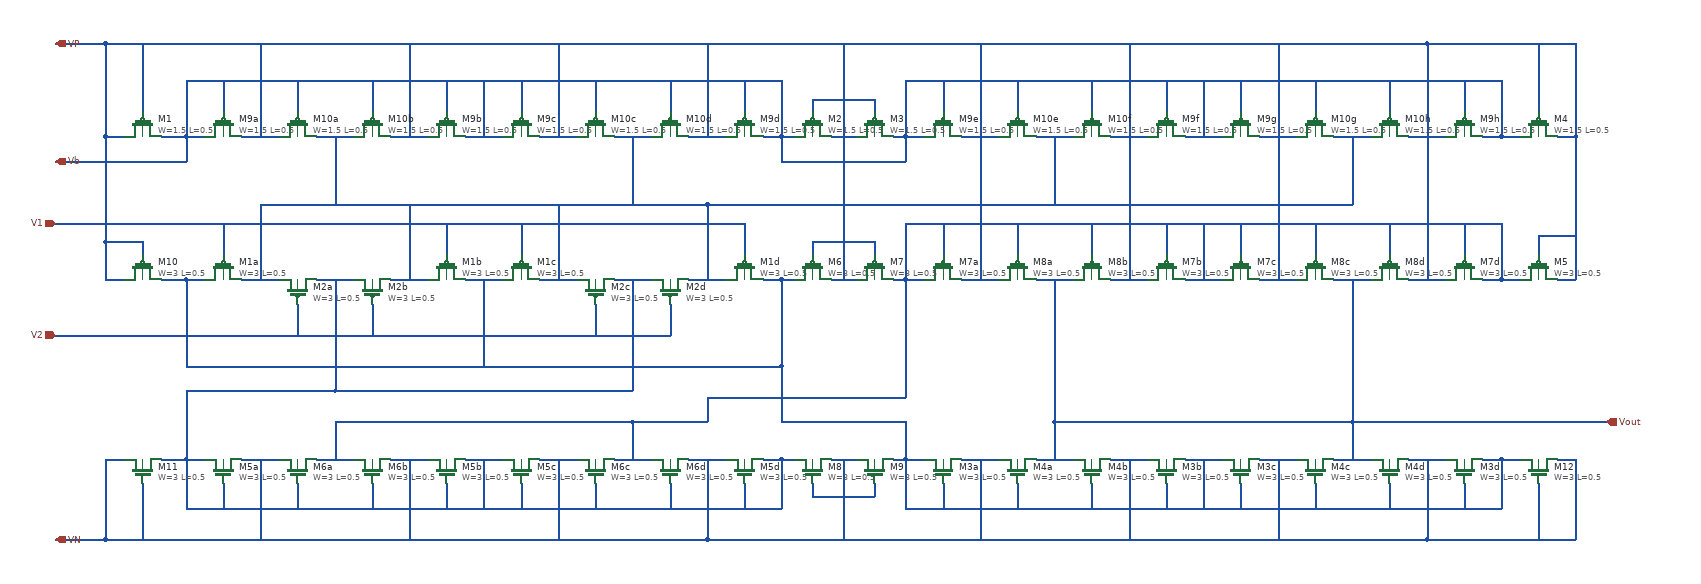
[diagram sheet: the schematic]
v {xschem version=3.4.5 file_version=1.2
}
G {}
K {}
V {}
S {}
E {}
N 470 -560 530 -560 {
lab=#net1}
N 590 -560 650 -560 {
lab=#net2}
N 710 -560 770 -560 {
lab=#net1}
N 950 -560 1010 -560 {
lab=#net1}
N 1070 -560 1130 -560 {
lab=#net2}
N 1190 -560 1260 -560 {
lab=#net1}
N 1310 -560 1340 -560 {
lab=#net3}
N 380 -560 410 -560 {
lab=#net3}
N 830 -560 890 -560 {
lab=#net3}
N 500 -680 500 -560 {
lab=#net1}
N 1220 -680 1220 -560 {
lab=#net1}
N 500 -680 1220 -680 {
lab=#net1}
N 740 -680 740 -560 {
lab=#net1}
N 980 -680 980 -560 {
lab=#net1}
N 800 -650 800 -600 {
lab=V1}
N 920 -650 920 -600 {
lab=V1}
N 1160 -520 1160 -470 {
lab=V2}
N 1040 -520 1040 -470 {
lab=V2}
N 680 -520 680 -470 {
lab=V2}
N 560 -520 560 -470 {
lab=V2}
N 1280 -650 1280 -600 {
lab=V1}
N 620 -380 1100 -380 {
lab=#net2}
N 470 -270 530 -270 {
lab=VN}
N 590 -270 650 -270 {
lab=#net4}
N 710 -270 770 -270 {
lab=VN}
N 830 -270 890 -270 {
lab=#net2}
N 950 -270 1010 -270 {
lab=VN}
N 1070 -270 1130 -270 {
lab=#net4}
N 1190 -270 1250 -270 {
lab=VN}
N 380 -270 410 -270 {
lab=#net2}
N 380 -270 380 -190 {
lab=#net2}
N 380 -190 1340 -190 {
lab=#net2}
N 1310 -270 1340 -270 {
lab=#net2}
N 1340 -270 1340 -190 {
lab=#net2}
N 440 -230 440 -190 {
lab=#net2}
N 560 -230 560 -190 {
lab=#net2}
N 680 -230 680 -190 {
lab=#net2}
N 800 -230 800 -190 {
lab=#net2}
N 920 -230 920 -190 {
lab=#net2}
N 1040 -230 1040 -190 {
lab=#net2}
N 1160 -230 1160 -190 {
lab=#net2}
N 1280 -230 1280 -190 {
lab=#net2}
N 860 -270 860 -190 {
lab=#net2}
N 1220 -270 1220 -140 {
lab=VN}
N 350 -140 1220 -140 {
lab=VN}
N 980 -270 980 -140 {
lab=VN}
N 740 -270 740 -140 {
lab=VN}
N 500 -270 500 -140 {
lab=VN}
N 620 -330 620 -270 {
lab=#net4}
N 620 -330 1100 -330 {
lab=#net4}
N 1100 -330 1100 -270 {
lab=#net4}
N 380 -380 620 -380 {
lab=#net2}
N 380 -560 380 -420 {
lab=#net3}
N 380 -420 1340 -420 {
lab=#net3}
N 1340 -560 1340 -420 {
lab=#net3}
N 860 -560 860 -420 {
lab=#net3}
N 620 -560 620 -380 {
lab=#net2}
N 380 -380 380 -270 {
lab=#net2}
N 1100 -560 1100 -380 {
lab=#net2}
N 1630 -270 1690 -270 {
lab=VN}
N 1750 -270 1810 -270 {
lab=Vout}
N 1870 -270 1930 -270 {
lab=VN}
N 1990 -270 2050 -270 {
lab=#net3}
N 2110 -270 2170 -270 {
lab=VN}
N 2230 -270 2290 -270 {
lab=Vout}
N 2350 -270 2410 -270 {
lab=VN}
N 1540 -270 1570 -270 {
lab=#net3}
N 1540 -270 1540 -190 {
lab=#net3}
N 1540 -190 2500 -190 {
lab=#net3}
N 2470 -270 2500 -270 {
lab=#net3}
N 2500 -270 2500 -190 {
lab=#net3}
N 1600 -230 1600 -190 {
lab=#net3}
N 1720 -230 1720 -190 {
lab=#net3}
N 1840 -230 1840 -190 {
lab=#net3}
N 1960 -230 1960 -190 {
lab=#net3}
N 2080 -230 2080 -190 {
lab=#net3}
N 2200 -230 2200 -190 {
lab=#net3}
N 2320 -230 2320 -190 {
lab=#net3}
N 2440 -230 2440 -190 {
lab=#net3}
N 2020 -270 2020 -190 {
lab=#net3}
N 1780 -330 1780 -270 {
lab=Vout}
N 1780 -330 2260 -330 {
lab=Vout}
N 2260 -330 2260 -270 {
lab=Vout}
N 1220 -140 2380 -140 {
lab=VN}
N 2380 -270 2380 -140 {
lab=VN}
N 2140 -270 2140 -140 {
lab=VN}
N 1900 -270 1900 -140 {
lab=VN}
N 1660 -270 1660 -140 {
lab=VN}
N 1630 -560 1690 -560 {
lab=VP}
N 1750 -560 1820 -560 {
lab=Vout}
N 1870 -560 1930 -560 {
lab=VP}
N 2110 -560 2170 -560 {
lab=VP}
N 2230 -560 2300 -560 {
lab=Vout}
N 2350 -560 2410 -560 {
lab=VP}
N 1990 -560 2050 -560 {
lab=#net4}
N 2470 -560 2500 -560 {
lab=#net4}
N 1540 -650 2500 -650 {
lab=#net4}
N 1540 -560 1570 -560 {
lab=#net4}
N 2260 -560 2260 -330 {
lab=Vout}
N 1780 -560 1780 -330 {
lab=Vout}
N 1540 -650 1540 -560 {
lab=#net4}
N 2500 -650 2500 -560 {
lab=#net4}
N 2440 -650 2440 -600 {
lab=#net4}
N 2320 -650 2320 -600 {
lab=#net4}
N 2020 -650 2020 -560 {
lab=#net4}
N 2080 -650 2080 -600 {
lab=#net4}
N 2200 -650 2200 -600 {
lab=#net4}
N 1960 -650 1960 -600 {
lab=#net4}
N 1840 -650 1840 -600 {
lab=#net4}
N 1720 -650 1720 -600 {
lab=#net4}
N 1600 -650 1600 -600 {
lab=#net4}
N 470 -790 530 -790 {
lab=VP}
N 590 -790 660 -790 {
lab=#net1}
N 710 -790 770 -790 {
lab=VP}
N 950 -790 1010 -790 {
lab=VP}
N 1070 -790 1140 -790 {
lab=#net1}
N 1190 -790 1250 -790 {
lab=VP}
N 830 -790 890 -790 {
lab=Vb}
N 1310 -790 1340 -790 {
lab=Vb}
N 380 -880 1340 -880 {
lab=Vb}
N 380 -790 410 -790 {
lab=Vb}
N 380 -880 380 -790 {
lab=Vb}
N 1340 -880 1340 -790 {
lab=Vb}
N 1280 -880 1280 -830 {
lab=Vb}
N 1160 -880 1160 -830 {
lab=Vb}
N 860 -880 860 -790 {
lab=Vb}
N 920 -880 920 -830 {
lab=Vb}
N 1040 -880 1040 -830 {
lab=Vb}
N 800 -880 800 -830 {
lab=Vb}
N 680 -880 680 -830 {
lab=Vb}
N 560 -880 560 -830 {
lab=Vb}
N 440 -880 440 -830 {
lab=Vb}
N 1630 -790 1690 -790 {
lab=VP}
N 1750 -790 1820 -790 {
lab=#net1}
N 1870 -790 1930 -790 {
lab=VP}
N 2110 -790 2170 -790 {
lab=VP}
N 2230 -790 2300 -790 {
lab=#net1}
N 2350 -790 2410 -790 {
lab=VP}
N 1990 -790 2050 -790 {
lab=Vb}
N 2470 -790 2500 -790 {
lab=Vb}
N 1540 -880 2500 -880 {
lab=Vb}
N 1540 -790 1570 -790 {
lab=Vb}
N 1540 -880 1540 -790 {
lab=Vb}
N 2500 -880 2500 -790 {
lab=Vb}
N 2440 -880 2440 -830 {
lab=Vb}
N 2320 -880 2320 -830 {
lab=Vb}
N 2020 -880 2020 -790 {
lab=Vb}
N 2080 -880 2080 -830 {
lab=Vb}
N 2200 -880 2200 -830 {
lab=Vb}
N 1960 -880 1960 -830 {
lab=Vb}
N 1840 -880 1840 -830 {
lab=Vb}
N 1720 -880 1720 -830 {
lab=Vb}
N 1600 -880 1600 -830 {
lab=Vb}
N 620 -790 620 -680 {
lab=#net1}
N 1100 -790 1100 -680 {
lab=#net1}
N 1220 -680 2260 -680 {
lab=#net1}
N 2260 -790 2260 -680 {
lab=#net1}
N 1780 -790 1780 -680 {
lab=#net1}
N 1340 -790 1340 -750 {
lab=Vb}
N 1340 -750 1540 -750 {
lab=Vb}
N 1540 -790 1540 -750 {
lab=Vb}
N 380 -790 380 -750 {
lab=Vb}
N 350 -940 2380 -940 {
lab=VP}
N 2380 -940 2380 -790 {
lab=VP}
N 2380 -790 2380 -560 {
lab=VP}
N 2140 -940 2140 -790 {
lab=VP}
N 2140 -790 2140 -560 {
lab=VP}
N 1900 -940 1900 -790 {
lab=VP}
N 1900 -790 1900 -560 {
lab=VP}
N 1660 -790 1660 -560 {
lab=VP}
N 1660 -940 1660 -790 {
lab=VP}
N 1220 -940 1220 -790 {
lab=VP}
N 980 -940 980 -790 {
lab=VP}
N 740 -940 740 -790 {
lab=VP}
N 500 -940 500 -790 {
lab=VP}
N 340 -790 380 -790 {
lab=Vb}
N 250 -940 350 -940 {
lab=VP}
N 310 -940 310 -830 {
lab=VP}
N 250 -140 350 -140 {
lab=VN}
N 1420 -790 1460 -790 {
lab=VP}
N 1520 -790 1540 -790 {
lab=Vb}
N 1340 -790 1360 -790 {
lab=Vb}
N 1390 -850 1390 -830 {
lab=VP}
N 1390 -850 1490 -850 {
lab=VP}
N 1490 -850 1490 -830 {
lab=VP}
N 1440 -850 1440 -790 {
lab=VP}
N 1440 -940 1440 -850 {
lab=VP}
N 2500 -790 2530 -790 {
lab=Vb}
N 2590 -790 2620 -790 {
lab=VP}
N 2380 -940 2620 -940 {
lab=VP}
N 2620 -940 2620 -790 {
lab=VP}
N 2560 -940 2560 -830 {
lab=VP}
N 2500 -560 2530 -560 {
lab=#net4}
N 2590 -560 2620 -560 {
lab=VP}
N 2620 -790 2620 -560 {
lab=VP}
N 2560 -630 2560 -600 {
lab=VP}
N 2560 -630 2620 -630 {
lab=VP}
N 1420 -560 1460 -560 {
lab=VP}
N 1520 -560 1540 -560 {
lab=#net4}
N 1340 -560 1360 -560 {
lab=#net3}
N 1390 -620 1390 -600 {
lab=VP}
N 1390 -620 1490 -620 {
lab=VP}
N 1490 -620 1490 -600 {
lab=VP}
N 1440 -620 1440 -560 {
lab=VP}
N 1440 -790 1440 -620 {
lab=VP}
N 1340 -270 1360 -270 {
lab=#net2}
N 1520 -270 1540 -270 {
lab=#net3}
N 1420 -270 1460 -270 {
lab=VN}
N 1390 -230 1390 -210 {
lab=VN}
N 1390 -210 1490 -210 {
lab=VN}
N 1490 -230 1490 -210 {
lab=VN}
N 1440 -270 1440 -210 {
lab=VN}
N 1440 -210 1440 -140 {
lab=VN}
N 1100 -330 1220 -330 {
lab=#net4}
N 1220 -370 1220 -330 {
lab=#net4}
N 1220 -370 1540 -370 {
lab=#net4}
N 1540 -560 1540 -370 {
lab=#net4}
N 1340 -420 1340 -330 {
lab=#net3}
N 1340 -330 1540 -330 {
lab=#net3}
N 1540 -330 1540 -270 {
lab=#net3}
N 250 -270 280 -270 {
lab=VN}
N 340 -270 380 -270 {
lab=#net2}
N 340 -560 380 -560 {
lab=#net3}
N 250 -560 280 -560 {
lab=VP}
N 250 -620 250 -560 {
lab=VP}
N 250 -620 310 -620 {
lab=VP}
N 310 -620 310 -600 {
lab=VP}
N 170 -940 250 -940 {
lab=VP}
N 170 -140 250 -140 {
lab=VN}
N 250 -790 280 -790 {
lab=VP}
N 250 -940 250 -790 {
lab=VP}
N 250 -790 250 -620 {
lab=VP}
N 170 -750 380 -750 {
lab=Vb}
N 310 -230 310 -140 {
lab=VN}
N 250 -270 250 -140 {
lab=VN}
N 2500 -270 2530 -270 {
lab=#net3}
N 2590 -270 2620 -270 {
lab=VN}
N 2620 -270 2620 -140 {
lab=VN}
N 2380 -140 2620 -140 {
lab=VN}
N 2560 -230 2560 -140 {
lab=VN}
N 2260 -330 2670 -330 {
lab=Vout}
N 170 -650 1280 -650 {
lab=V1}
N 170 -470 1160 -470 {
lab=V2}
N 440 -650 440 -600 {
lab=V1}
C {sky130_fd_pr/pfet3_01v8.sym} 440 -580 1 0 {name=M1a
L=0.5
W=3
body=VP
nf=1
mult=1
ad="'int((nf+1)/2) * W/nf * 0.29'" 
pd="'2*int((nf+1)/2) * (W/nf + 0.29)'"
as="'int((nf+2)/2) * W/nf * 0.29'" 
ps="'2*int((nf+2)/2) * (W/nf + 0.29)'"
nrd="'0.29 / W'" nrs="'0.29 / W'"
sa=0 sb=0 sd=0
model=pfet_01v8
spiceprefix=X
}
C {sky130_fd_pr/pfet3_01v8.sym} 560 -540 3 0 {name=M2a
L=0.5
W=3
body=VP
nf=1
mult=1
ad="'int((nf+1)/2) * W/nf * 0.29'" 
pd="'2*int((nf+1)/2) * (W/nf + 0.29)'"
as="'int((nf+2)/2) * W/nf * 0.29'" 
ps="'2*int((nf+2)/2) * (W/nf + 0.29)'"
nrd="'0.29 / W'" nrs="'0.29 / W'"
sa=0 sb=0 sd=0
model=pfet_01v8
spiceprefix=X
}
C {sky130_fd_pr/pfet3_01v8.sym} 680 -540 3 0 {name=M2b
L=0.5
W=3
body=VP
nf=1
mult=1
ad="'int((nf+1)/2) * W/nf * 0.29'" 
pd="'2*int((nf+1)/2) * (W/nf + 0.29)'"
as="'int((nf+2)/2) * W/nf * 0.29'" 
ps="'2*int((nf+2)/2) * (W/nf + 0.29)'"
nrd="'0.29 / W'" nrs="'0.29 / W'"
sa=0 sb=0 sd=0
model=pfet_01v8
spiceprefix=X
}
C {sky130_fd_pr/pfet3_01v8.sym} 800 -580 1 0 {name=M1b
L=0.5
W=3
body=VP
nf=1
mult=1
ad="'int((nf+1)/2) * W/nf * 0.29'" 
pd="'2*int((nf+1)/2) * (W/nf + 0.29)'"
as="'int((nf+2)/2) * W/nf * 0.29'" 
ps="'2*int((nf+2)/2) * (W/nf + 0.29)'"
nrd="'0.29 / W'" nrs="'0.29 / W'"
sa=0 sb=0 sd=0
model=pfet_01v8
spiceprefix=X
}
C {sky130_fd_pr/pfet3_01v8.sym} 920 -580 1 0 {name=M1c
L=0.5
W=3
body=VP
nf=1
mult=1
ad="'int((nf+1)/2) * W/nf * 0.29'" 
pd="'2*int((nf+1)/2) * (W/nf + 0.29)'"
as="'int((nf+2)/2) * W/nf * 0.29'" 
ps="'2*int((nf+2)/2) * (W/nf + 0.29)'"
nrd="'0.29 / W'" nrs="'0.29 / W'"
sa=0 sb=0 sd=0
model=pfet_01v8
spiceprefix=X
}
C {sky130_fd_pr/pfet3_01v8.sym} 1040 -540 3 0 {name=M2c
L=0.5
W=3
body=VP
nf=1
mult=1
ad="'int((nf+1)/2) * W/nf * 0.29'" 
pd="'2*int((nf+1)/2) * (W/nf + 0.29)'"
as="'int((nf+2)/2) * W/nf * 0.29'" 
ps="'2*int((nf+2)/2) * (W/nf + 0.29)'"
nrd="'0.29 / W'" nrs="'0.29 / W'"
sa=0 sb=0 sd=0
model=pfet_01v8
spiceprefix=X
}
C {sky130_fd_pr/pfet3_01v8.sym} 1160 -540 3 0 {name=M2d
L=0.5
W=3
body=VP
nf=1
mult=1
ad="'int((nf+1)/2) * W/nf * 0.29'" 
pd="'2*int((nf+1)/2) * (W/nf + 0.29)'"
as="'int((nf+2)/2) * W/nf * 0.29'" 
ps="'2*int((nf+2)/2) * (W/nf + 0.29)'"
nrd="'0.29 / W'" nrs="'0.29 / W'"
sa=0 sb=0 sd=0
model=pfet_01v8
spiceprefix=X
}
C {sky130_fd_pr/pfet3_01v8.sym} 1280 -580 1 0 {name=M1d
L=0.5
W=3
body=VP
nf=1
mult=1
ad="'int((nf+1)/2) * W/nf * 0.29'" 
pd="'2*int((nf+1)/2) * (W/nf + 0.29)'"
as="'int((nf+2)/2) * W/nf * 0.29'" 
ps="'2*int((nf+2)/2) * (W/nf + 0.29)'"
nrd="'0.29 / W'" nrs="'0.29 / W'"
sa=0 sb=0 sd=0
model=pfet_01v8
spiceprefix=X
}
C {sky130_fd_pr/nfet3_01v8.sym} 440 -250 3 0 {name=M5a
L=0.5
W=3
body=VN
nf=1
mult=1
ad="'int((nf+1)/2) * W/nf * 0.29'" 
pd="'2*int((nf+1)/2) * (W/nf + 0.29)'"
as="'int((nf+2)/2) * W/nf * 0.29'" 
ps="'2*int((nf+2)/2) * (W/nf + 0.29)'"
nrd="'0.29 / W'" nrs="'0.29 / W'"
sa=0 sb=0 sd=0
model=nfet_01v8
spiceprefix=X
}
C {sky130_fd_pr/nfet3_01v8.sym} 560 -250 3 0 {name=M6a
L=0.5
W=3
body=VN
nf=1
mult=1
ad="'int((nf+1)/2) * W/nf * 0.29'" 
pd="'2*int((nf+1)/2) * (W/nf + 0.29)'"
as="'int((nf+2)/2) * W/nf * 0.29'" 
ps="'2*int((nf+2)/2) * (W/nf + 0.29)'"
nrd="'0.29 / W'" nrs="'0.29 / W'"
sa=0 sb=0 sd=0
model=nfet_01v8
spiceprefix=X
}
C {sky130_fd_pr/nfet3_01v8.sym} 680 -250 3 0 {name=M6b
L=0.5
W=3
body=VN
nf=1
mult=1
ad="'int((nf+1)/2) * W/nf * 0.29'" 
pd="'2*int((nf+1)/2) * (W/nf + 0.29)'"
as="'int((nf+2)/2) * W/nf * 0.29'" 
ps="'2*int((nf+2)/2) * (W/nf + 0.29)'"
nrd="'0.29 / W'" nrs="'0.29 / W'"
sa=0 sb=0 sd=0
model=nfet_01v8
spiceprefix=X
}
C {sky130_fd_pr/nfet3_01v8.sym} 800 -250 3 0 {name=M5b
L=0.5
W=3
body=VN
nf=1
mult=1
ad="'int((nf+1)/2) * W/nf * 0.29'" 
pd="'2*int((nf+1)/2) * (W/nf + 0.29)'"
as="'int((nf+2)/2) * W/nf * 0.29'" 
ps="'2*int((nf+2)/2) * (W/nf + 0.29)'"
nrd="'0.29 / W'" nrs="'0.29 / W'"
sa=0 sb=0 sd=0
model=nfet_01v8
spiceprefix=X
}
C {sky130_fd_pr/nfet3_01v8.sym} 920 -250 3 0 {name=M5c
L=0.5
W=3
body=VN
nf=1
mult=1
ad="'int((nf+1)/2) * W/nf * 0.29'" 
pd="'2*int((nf+1)/2) * (W/nf + 0.29)'"
as="'int((nf+2)/2) * W/nf * 0.29'" 
ps="'2*int((nf+2)/2) * (W/nf + 0.29)'"
nrd="'0.29 / W'" nrs="'0.29 / W'"
sa=0 sb=0 sd=0
model=nfet_01v8
spiceprefix=X
}
C {sky130_fd_pr/nfet3_01v8.sym} 1040 -250 3 0 {name=M6c
L=0.5
W=3
body=VN
nf=1
mult=1
ad="'int((nf+1)/2) * W/nf * 0.29'" 
pd="'2*int((nf+1)/2) * (W/nf + 0.29)'"
as="'int((nf+2)/2) * W/nf * 0.29'" 
ps="'2*int((nf+2)/2) * (W/nf + 0.29)'"
nrd="'0.29 / W'" nrs="'0.29 / W'"
sa=0 sb=0 sd=0
model=nfet_01v8
spiceprefix=X
}
C {sky130_fd_pr/nfet3_01v8.sym} 1160 -250 3 0 {name=M6d
L=0.5
W=3
body=VN
nf=1
mult=1
ad="'int((nf+1)/2) * W/nf * 0.29'" 
pd="'2*int((nf+1)/2) * (W/nf + 0.29)'"
as="'int((nf+2)/2) * W/nf * 0.29'" 
ps="'2*int((nf+2)/2) * (W/nf + 0.29)'"
nrd="'0.29 / W'" nrs="'0.29 / W'"
sa=0 sb=0 sd=0
model=nfet_01v8
spiceprefix=X
}
C {sky130_fd_pr/nfet3_01v8.sym} 1280 -250 3 0 {name=M5d
L=0.5
W=3
body=VN
nf=1
mult=1
ad="'int((nf+1)/2) * W/nf * 0.29'" 
pd="'2*int((nf+1)/2) * (W/nf + 0.29)'"
as="'int((nf+2)/2) * W/nf * 0.29'" 
ps="'2*int((nf+2)/2) * (W/nf + 0.29)'"
nrd="'0.29 / W'" nrs="'0.29 / W'"
sa=0 sb=0 sd=0
model=nfet_01v8
spiceprefix=X
}
C {sky130_fd_pr/nfet3_01v8.sym} 1600 -250 3 0 {name=M3a
L=0.5
W=3
body=VN
nf=1
mult=1
ad="'int((nf+1)/2) * W/nf * 0.29'" 
pd="'2*int((nf+1)/2) * (W/nf + 0.29)'"
as="'int((nf+2)/2) * W/nf * 0.29'" 
ps="'2*int((nf+2)/2) * (W/nf + 0.29)'"
nrd="'0.29 / W'" nrs="'0.29 / W'"
sa=0 sb=0 sd=0
model=nfet_01v8
spiceprefix=X
}
C {sky130_fd_pr/nfet3_01v8.sym} 1720 -250 3 0 {name=M4a
L=0.5
W=3
body=VN
nf=1
mult=1
ad="'int((nf+1)/2) * W/nf * 0.29'" 
pd="'2*int((nf+1)/2) * (W/nf + 0.29)'"
as="'int((nf+2)/2) * W/nf * 0.29'" 
ps="'2*int((nf+2)/2) * (W/nf + 0.29)'"
nrd="'0.29 / W'" nrs="'0.29 / W'"
sa=0 sb=0 sd=0
model=nfet_01v8
spiceprefix=X
}
C {sky130_fd_pr/nfet3_01v8.sym} 1840 -250 3 0 {name=M4b
L=0.5
W=3
body=VN
nf=1
mult=1
ad="'int((nf+1)/2) * W/nf * 0.29'" 
pd="'2*int((nf+1)/2) * (W/nf + 0.29)'"
as="'int((nf+2)/2) * W/nf * 0.29'" 
ps="'2*int((nf+2)/2) * (W/nf + 0.29)'"
nrd="'0.29 / W'" nrs="'0.29 / W'"
sa=0 sb=0 sd=0
model=nfet_01v8
spiceprefix=X
}
C {sky130_fd_pr/nfet3_01v8.sym} 1960 -250 3 0 {name=M3b
L=0.5
W=3
body=VN
nf=1
mult=1
ad="'int((nf+1)/2) * W/nf * 0.29'" 
pd="'2*int((nf+1)/2) * (W/nf + 0.29)'"
as="'int((nf+2)/2) * W/nf * 0.29'" 
ps="'2*int((nf+2)/2) * (W/nf + 0.29)'"
nrd="'0.29 / W'" nrs="'0.29 / W'"
sa=0 sb=0 sd=0
model=nfet_01v8
spiceprefix=X
}
C {sky130_fd_pr/nfet3_01v8.sym} 2080 -250 3 0 {name=M3c
L=0.5
W=3
body=VN
nf=1
mult=1
ad="'int((nf+1)/2) * W/nf * 0.29'" 
pd="'2*int((nf+1)/2) * (W/nf + 0.29)'"
as="'int((nf+2)/2) * W/nf * 0.29'" 
ps="'2*int((nf+2)/2) * (W/nf + 0.29)'"
nrd="'0.29 / W'" nrs="'0.29 / W'"
sa=0 sb=0 sd=0
model=nfet_01v8
spiceprefix=X
}
C {sky130_fd_pr/nfet3_01v8.sym} 2200 -250 3 0 {name=M4c
L=0.5
W=3
body=VN
nf=1
mult=1
ad="'int((nf+1)/2) * W/nf * 0.29'" 
pd="'2*int((nf+1)/2) * (W/nf + 0.29)'"
as="'int((nf+2)/2) * W/nf * 0.29'" 
ps="'2*int((nf+2)/2) * (W/nf + 0.29)'"
nrd="'0.29 / W'" nrs="'0.29 / W'"
sa=0 sb=0 sd=0
model=nfet_01v8
spiceprefix=X
}
C {sky130_fd_pr/nfet3_01v8.sym} 2320 -250 3 0 {name=M4d
L=0.5
W=3
body=VN
nf=1
mult=1
ad="'int((nf+1)/2) * W/nf * 0.29'" 
pd="'2*int((nf+1)/2) * (W/nf + 0.29)'"
as="'int((nf+2)/2) * W/nf * 0.29'" 
ps="'2*int((nf+2)/2) * (W/nf + 0.29)'"
nrd="'0.29 / W'" nrs="'0.29 / W'"
sa=0 sb=0 sd=0
model=nfet_01v8
spiceprefix=X
}
C {sky130_fd_pr/nfet3_01v8.sym} 2440 -250 3 0 {name=M3d
L=0.5
W=3
body=VN
nf=1
mult=1
ad="'int((nf+1)/2) * W/nf * 0.29'" 
pd="'2*int((nf+1)/2) * (W/nf + 0.29)'"
as="'int((nf+2)/2) * W/nf * 0.29'" 
ps="'2*int((nf+2)/2) * (W/nf + 0.29)'"
nrd="'0.29 / W'" nrs="'0.29 / W'"
sa=0 sb=0 sd=0
model=nfet_01v8
spiceprefix=X
}
C {sky130_fd_pr/pfet3_01v8.sym} 1600 -580 1 0 {name=M7a
L=0.5
W=3
body=VP
nf=1
mult=1
ad="'int((nf+1)/2) * W/nf * 0.29'" 
pd="'2*int((nf+1)/2) * (W/nf + 0.29)'"
as="'int((nf+2)/2) * W/nf * 0.29'" 
ps="'2*int((nf+2)/2) * (W/nf + 0.29)'"
nrd="'0.29 / W'" nrs="'0.29 / W'"
sa=0 sb=0 sd=0
model=pfet_01v8
spiceprefix=X
}
C {sky130_fd_pr/pfet3_01v8.sym} 1720 -580 1 0 {name=M8a
L=0.5
W=3
body=VP
nf=1
mult=1
ad="'int((nf+1)/2) * W/nf * 0.29'" 
pd="'2*int((nf+1)/2) * (W/nf + 0.29)'"
as="'int((nf+2)/2) * W/nf * 0.29'" 
ps="'2*int((nf+2)/2) * (W/nf + 0.29)'"
nrd="'0.29 / W'" nrs="'0.29 / W'"
sa=0 sb=0 sd=0
model=pfet_01v8
spiceprefix=X
}
C {sky130_fd_pr/pfet3_01v8.sym} 1840 -580 1 0 {name=M8b
L=0.5
W=3
body=VP
nf=1
mult=1
ad="'int((nf+1)/2) * W/nf * 0.29'" 
pd="'2*int((nf+1)/2) * (W/nf + 0.29)'"
as="'int((nf+2)/2) * W/nf * 0.29'" 
ps="'2*int((nf+2)/2) * (W/nf + 0.29)'"
nrd="'0.29 / W'" nrs="'0.29 / W'"
sa=0 sb=0 sd=0
model=pfet_01v8
spiceprefix=X
}
C {sky130_fd_pr/pfet3_01v8.sym} 1960 -580 1 0 {name=M7b
L=0.5
W=3
body=VP
nf=1
mult=1
ad="'int((nf+1)/2) * W/nf * 0.29'" 
pd="'2*int((nf+1)/2) * (W/nf + 0.29)'"
as="'int((nf+2)/2) * W/nf * 0.29'" 
ps="'2*int((nf+2)/2) * (W/nf + 0.29)'"
nrd="'0.29 / W'" nrs="'0.29 / W'"
sa=0 sb=0 sd=0
model=pfet_01v8
spiceprefix=X
}
C {sky130_fd_pr/pfet3_01v8.sym} 2080 -580 1 0 {name=M7c
L=0.5
W=3
body=VP
nf=1
mult=1
ad="'int((nf+1)/2) * W/nf * 0.29'" 
pd="'2*int((nf+1)/2) * (W/nf + 0.29)'"
as="'int((nf+2)/2) * W/nf * 0.29'" 
ps="'2*int((nf+2)/2) * (W/nf + 0.29)'"
nrd="'0.29 / W'" nrs="'0.29 / W'"
sa=0 sb=0 sd=0
model=pfet_01v8
spiceprefix=X
}
C {sky130_fd_pr/pfet3_01v8.sym} 2200 -580 1 0 {name=M8c
L=0.5
W=3
body=VP
nf=1
mult=1
ad="'int((nf+1)/2) * W/nf * 0.29'" 
pd="'2*int((nf+1)/2) * (W/nf + 0.29)'"
as="'int((nf+2)/2) * W/nf * 0.29'" 
ps="'2*int((nf+2)/2) * (W/nf + 0.29)'"
nrd="'0.29 / W'" nrs="'0.29 / W'"
sa=0 sb=0 sd=0
model=pfet_01v8
spiceprefix=X
}
C {sky130_fd_pr/pfet3_01v8.sym} 2320 -580 1 0 {name=M8d
L=0.5
W=3
body=VP
nf=1
mult=1
ad="'int((nf+1)/2) * W/nf * 0.29'" 
pd="'2*int((nf+1)/2) * (W/nf + 0.29)'"
as="'int((nf+2)/2) * W/nf * 0.29'" 
ps="'2*int((nf+2)/2) * (W/nf + 0.29)'"
nrd="'0.29 / W'" nrs="'0.29 / W'"
sa=0 sb=0 sd=0
model=pfet_01v8
spiceprefix=X
}
C {sky130_fd_pr/pfet3_01v8.sym} 2440 -580 1 0 {name=M7d
L=0.5
W=3
body=VP
nf=1
mult=1
ad="'int((nf+1)/2) * W/nf * 0.29'" 
pd="'2*int((nf+1)/2) * (W/nf + 0.29)'"
as="'int((nf+2)/2) * W/nf * 0.29'" 
ps="'2*int((nf+2)/2) * (W/nf + 0.29)'"
nrd="'0.29 / W'" nrs="'0.29 / W'"
sa=0 sb=0 sd=0
model=pfet_01v8
spiceprefix=X
}
C {sky130_fd_pr/pfet3_01v8.sym} 440 -810 1 0 {name=M9a
L=0.5
W=1.5
body=VP
nf=1
mult=1
ad="'int((nf+1)/2) * W/nf * 0.29'" 
pd="'2*int((nf+1)/2) * (W/nf + 0.29)'"
as="'int((nf+2)/2) * W/nf * 0.29'" 
ps="'2*int((nf+2)/2) * (W/nf + 0.29)'"
nrd="'0.29 / W'" nrs="'0.29 / W'"
sa=0 sb=0 sd=0
model=pfet_01v8
spiceprefix=X
}
C {sky130_fd_pr/pfet3_01v8.sym} 560 -810 1 0 {name=M10a
L=0.5
W=1.5
body=VP
nf=1
mult=1
ad="'int((nf+1)/2) * W/nf * 0.29'" 
pd="'2*int((nf+1)/2) * (W/nf + 0.29)'"
as="'int((nf+2)/2) * W/nf * 0.29'" 
ps="'2*int((nf+2)/2) * (W/nf + 0.29)'"
nrd="'0.29 / W'" nrs="'0.29 / W'"
sa=0 sb=0 sd=0
model=pfet_01v8
spiceprefix=X
}
C {sky130_fd_pr/pfet3_01v8.sym} 680 -810 1 0 {name=M10b
L=0.5
W=1.5
body=VP
nf=1
mult=1
ad="'int((nf+1)/2) * W/nf * 0.29'" 
pd="'2*int((nf+1)/2) * (W/nf + 0.29)'"
as="'int((nf+2)/2) * W/nf * 0.29'" 
ps="'2*int((nf+2)/2) * (W/nf + 0.29)'"
nrd="'0.29 / W'" nrs="'0.29 / W'"
sa=0 sb=0 sd=0
model=pfet_01v8
spiceprefix=X
}
C {sky130_fd_pr/pfet3_01v8.sym} 800 -810 1 0 {name=M9b
L=0.5
W=1.5
body=VP
nf=1
mult=1
ad="'int((nf+1)/2) * W/nf * 0.29'" 
pd="'2*int((nf+1)/2) * (W/nf + 0.29)'"
as="'int((nf+2)/2) * W/nf * 0.29'" 
ps="'2*int((nf+2)/2) * (W/nf + 0.29)'"
nrd="'0.29 / W'" nrs="'0.29 / W'"
sa=0 sb=0 sd=0
model=pfet_01v8
spiceprefix=X
}
C {sky130_fd_pr/pfet3_01v8.sym} 920 -810 1 0 {name=M9c
L=0.5
W=1.5
body=VP
nf=1
mult=1
ad="'int((nf+1)/2) * W/nf * 0.29'" 
pd="'2*int((nf+1)/2) * (W/nf + 0.29)'"
as="'int((nf+2)/2) * W/nf * 0.29'" 
ps="'2*int((nf+2)/2) * (W/nf + 0.29)'"
nrd="'0.29 / W'" nrs="'0.29 / W'"
sa=0 sb=0 sd=0
model=pfet_01v8
spiceprefix=X
}
C {sky130_fd_pr/pfet3_01v8.sym} 1040 -810 1 0 {name=M10c
L=0.5
W=1.5
body=VP
nf=1
mult=1
ad="'int((nf+1)/2) * W/nf * 0.29'" 
pd="'2*int((nf+1)/2) * (W/nf + 0.29)'"
as="'int((nf+2)/2) * W/nf * 0.29'" 
ps="'2*int((nf+2)/2) * (W/nf + 0.29)'"
nrd="'0.29 / W'" nrs="'0.29 / W'"
sa=0 sb=0 sd=0
model=pfet_01v8
spiceprefix=X
}
C {sky130_fd_pr/pfet3_01v8.sym} 1160 -810 1 0 {name=M10d
L=0.5
W=1.5
body=VP
nf=1
mult=1
ad="'int((nf+1)/2) * W/nf * 0.29'" 
pd="'2*int((nf+1)/2) * (W/nf + 0.29)'"
as="'int((nf+2)/2) * W/nf * 0.29'" 
ps="'2*int((nf+2)/2) * (W/nf + 0.29)'"
nrd="'0.29 / W'" nrs="'0.29 / W'"
sa=0 sb=0 sd=0
model=pfet_01v8
spiceprefix=X
}
C {sky130_fd_pr/pfet3_01v8.sym} 1280 -810 1 0 {name=M9d
L=0.5
W=1.5
body=VP
nf=1
mult=1
ad="'int((nf+1)/2) * W/nf * 0.29'" 
pd="'2*int((nf+1)/2) * (W/nf + 0.29)'"
as="'int((nf+2)/2) * W/nf * 0.29'" 
ps="'2*int((nf+2)/2) * (W/nf + 0.29)'"
nrd="'0.29 / W'" nrs="'0.29 / W'"
sa=0 sb=0 sd=0
model=pfet_01v8
spiceprefix=X
}
C {sky130_fd_pr/pfet3_01v8.sym} 1600 -810 1 0 {name=M9e
L=0.5
W=1.5
body=VP
nf=1
mult=1
ad="'int((nf+1)/2) * W/nf * 0.29'" 
pd="'2*int((nf+1)/2) * (W/nf + 0.29)'"
as="'int((nf+2)/2) * W/nf * 0.29'" 
ps="'2*int((nf+2)/2) * (W/nf + 0.29)'"
nrd="'0.29 / W'" nrs="'0.29 / W'"
sa=0 sb=0 sd=0
model=pfet_01v8
spiceprefix=X
}
C {sky130_fd_pr/pfet3_01v8.sym} 1720 -810 1 0 {name=M10e
L=0.5
W=1.5
body=VP
nf=1
mult=1
ad="'int((nf+1)/2) * W/nf * 0.29'" 
pd="'2*int((nf+1)/2) * (W/nf + 0.29)'"
as="'int((nf+2)/2) * W/nf * 0.29'" 
ps="'2*int((nf+2)/2) * (W/nf + 0.29)'"
nrd="'0.29 / W'" nrs="'0.29 / W'"
sa=0 sb=0 sd=0
model=pfet_01v8
spiceprefix=X
}
C {sky130_fd_pr/pfet3_01v8.sym} 1840 -810 1 0 {name=M10f
L=0.5
W=1.5
body=VP
nf=1
mult=1
ad="'int((nf+1)/2) * W/nf * 0.29'" 
pd="'2*int((nf+1)/2) * (W/nf + 0.29)'"
as="'int((nf+2)/2) * W/nf * 0.29'" 
ps="'2*int((nf+2)/2) * (W/nf + 0.29)'"
nrd="'0.29 / W'" nrs="'0.29 / W'"
sa=0 sb=0 sd=0
model=pfet_01v8
spiceprefix=X
}
C {sky130_fd_pr/pfet3_01v8.sym} 1960 -810 1 0 {name=M9f
L=0.5
W=1.5
body=VP
nf=1
mult=1
ad="'int((nf+1)/2) * W/nf * 0.29'" 
pd="'2*int((nf+1)/2) * (W/nf + 0.29)'"
as="'int((nf+2)/2) * W/nf * 0.29'" 
ps="'2*int((nf+2)/2) * (W/nf + 0.29)'"
nrd="'0.29 / W'" nrs="'0.29 / W'"
sa=0 sb=0 sd=0
model=pfet_01v8
spiceprefix=X
}
C {sky130_fd_pr/pfet3_01v8.sym} 2080 -810 1 0 {name=M9g
L=0.5
W=1.5
body=VP
nf=1
mult=1
ad="'int((nf+1)/2) * W/nf * 0.29'" 
pd="'2*int((nf+1)/2) * (W/nf + 0.29)'"
as="'int((nf+2)/2) * W/nf * 0.29'" 
ps="'2*int((nf+2)/2) * (W/nf + 0.29)'"
nrd="'0.29 / W'" nrs="'0.29 / W'"
sa=0 sb=0 sd=0
model=pfet_01v8
spiceprefix=X
}
C {sky130_fd_pr/pfet3_01v8.sym} 2200 -810 1 0 {name=M10g
L=0.5
W=1.5
body=VP
nf=1
mult=1
ad="'int((nf+1)/2) * W/nf * 0.29'" 
pd="'2*int((nf+1)/2) * (W/nf + 0.29)'"
as="'int((nf+2)/2) * W/nf * 0.29'" 
ps="'2*int((nf+2)/2) * (W/nf + 0.29)'"
nrd="'0.29 / W'" nrs="'0.29 / W'"
sa=0 sb=0 sd=0
model=pfet_01v8
spiceprefix=X
}
C {sky130_fd_pr/pfet3_01v8.sym} 2320 -810 1 0 {name=M10h
L=0.5
W=1.5
body=VP
nf=1
mult=1
ad="'int((nf+1)/2) * W/nf * 0.29'" 
pd="'2*int((nf+1)/2) * (W/nf + 0.29)'"
as="'int((nf+2)/2) * W/nf * 0.29'" 
ps="'2*int((nf+2)/2) * (W/nf + 0.29)'"
nrd="'0.29 / W'" nrs="'0.29 / W'"
sa=0 sb=0 sd=0
model=pfet_01v8
spiceprefix=X
}
C {sky130_fd_pr/pfet3_01v8.sym} 2440 -810 1 0 {name=M9h
L=0.5
W=1.5
body=VP
nf=1
mult=1
ad="'int((nf+1)/2) * W/nf * 0.29'" 
pd="'2*int((nf+1)/2) * (W/nf + 0.29)'"
as="'int((nf+2)/2) * W/nf * 0.29'" 
ps="'2*int((nf+2)/2) * (W/nf + 0.29)'"
nrd="'0.29 / W'" nrs="'0.29 / W'"
sa=0 sb=0 sd=0
model=pfet_01v8
spiceprefix=X
}
C {sky130_fd_pr/pfet3_01v8.sym} 310 -810 1 0 {name=M1
L=0.5
W=1.5
body=VP
nf=1
mult=1
ad="'int((nf+1)/2) * W/nf * 0.29'" 
pd="'2*int((nf+1)/2) * (W/nf + 0.29)'"
as="'int((nf+2)/2) * W/nf * 0.29'" 
ps="'2*int((nf+2)/2) * (W/nf + 0.29)'"
nrd="'0.29 / W'" nrs="'0.29 / W'"
sa=0 sb=0 sd=0
model=pfet_01v8
spiceprefix=X
}
C {sky130_fd_pr/pfet3_01v8.sym} 1390 -810 1 0 {name=M2
L=0.5
W=1.5
body=VP
nf=1
mult=1
ad="'int((nf+1)/2) * W/nf * 0.29'" 
pd="'2*int((nf+1)/2) * (W/nf + 0.29)'"
as="'int((nf+2)/2) * W/nf * 0.29'" 
ps="'2*int((nf+2)/2) * (W/nf + 0.29)'"
nrd="'0.29 / W'" nrs="'0.29 / W'"
sa=0 sb=0 sd=0
model=pfet_01v8
spiceprefix=X
}
C {sky130_fd_pr/pfet3_01v8.sym} 1490 -810 1 0 {name=M3
L=0.5
W=1.5
body=VP
nf=1
mult=1
ad="'int((nf+1)/2) * W/nf * 0.29'" 
pd="'2*int((nf+1)/2) * (W/nf + 0.29)'"
as="'int((nf+2)/2) * W/nf * 0.29'" 
ps="'2*int((nf+2)/2) * (W/nf + 0.29)'"
nrd="'0.29 / W'" nrs="'0.29 / W'"
sa=0 sb=0 sd=0
model=pfet_01v8
spiceprefix=X
}
C {sky130_fd_pr/pfet3_01v8.sym} 2560 -810 1 0 {name=M4
L=0.5
W=1.5
body=VP
nf=1
mult=1
ad="'int((nf+1)/2) * W/nf * 0.29'" 
pd="'2*int((nf+1)/2) * (W/nf + 0.29)'"
as="'int((nf+2)/2) * W/nf * 0.29'" 
ps="'2*int((nf+2)/2) * (W/nf + 0.29)'"
nrd="'0.29 / W'" nrs="'0.29 / W'"
sa=0 sb=0 sd=0
model=pfet_01v8
spiceprefix=X
}
C {sky130_fd_pr/pfet3_01v8.sym} 2560 -580 1 0 {name=M5
L=0.5
W=3
body=VP
nf=1
mult=1
ad="'int((nf+1)/2) * W/nf * 0.29'" 
pd="'2*int((nf+1)/2) * (W/nf + 0.29)'"
as="'int((nf+2)/2) * W/nf * 0.29'" 
ps="'2*int((nf+2)/2) * (W/nf + 0.29)'"
nrd="'0.29 / W'" nrs="'0.29 / W'"
sa=0 sb=0 sd=0
model=pfet_01v8
spiceprefix=X
}
C {sky130_fd_pr/pfet3_01v8.sym} 1390 -580 1 0 {name=M6
L=0.5
W=3
body=VP
nf=1
mult=1
ad="'int((nf+1)/2) * W/nf * 0.29'" 
pd="'2*int((nf+1)/2) * (W/nf + 0.29)'"
as="'int((nf+2)/2) * W/nf * 0.29'" 
ps="'2*int((nf+2)/2) * (W/nf + 0.29)'"
nrd="'0.29 / W'" nrs="'0.29 / W'"
sa=0 sb=0 sd=0
model=pfet_01v8
spiceprefix=X
}
C {sky130_fd_pr/pfet3_01v8.sym} 1490 -580 1 0 {name=M7
L=0.5
W=3
body=VP
nf=1
mult=1
ad="'int((nf+1)/2) * W/nf * 0.29'" 
pd="'2*int((nf+1)/2) * (W/nf + 0.29)'"
as="'int((nf+2)/2) * W/nf * 0.29'" 
ps="'2*int((nf+2)/2) * (W/nf + 0.29)'"
nrd="'0.29 / W'" nrs="'0.29 / W'"
sa=0 sb=0 sd=0
model=pfet_01v8
spiceprefix=X
}
C {sky130_fd_pr/nfet3_01v8.sym} 1390 -250 3 0 {name=M8
L=0.5
W=3
body=VN
nf=1
mult=1
ad="'int((nf+1)/2) * W/nf * 0.29'" 
pd="'2*int((nf+1)/2) * (W/nf + 0.29)'"
as="'int((nf+2)/2) * W/nf * 0.29'" 
ps="'2*int((nf+2)/2) * (W/nf + 0.29)'"
nrd="'0.29 / W'" nrs="'0.29 / W'"
sa=0 sb=0 sd=0
model=nfet_01v8
spiceprefix=X
}
C {sky130_fd_pr/nfet3_01v8.sym} 1490 -250 3 0 {name=M9
L=0.5
W=3
body=VN
nf=1
mult=1
ad="'int((nf+1)/2) * W/nf * 0.29'" 
pd="'2*int((nf+1)/2) * (W/nf + 0.29)'"
as="'int((nf+2)/2) * W/nf * 0.29'" 
ps="'2*int((nf+2)/2) * (W/nf + 0.29)'"
nrd="'0.29 / W'" nrs="'0.29 / W'"
sa=0 sb=0 sd=0
model=nfet_01v8
spiceprefix=X
}
C {sky130_fd_pr/pfet3_01v8.sym} 310 -580 3 1 {name=M10
L=0.5
W=3
body=VP
nf=1
mult=1
ad="'int((nf+1)/2) * W/nf * 0.29'" 
pd="'2*int((nf+1)/2) * (W/nf + 0.29)'"
as="'int((nf+2)/2) * W/nf * 0.29'" 
ps="'2*int((nf+2)/2) * (W/nf + 0.29)'"
nrd="'0.29 / W'" nrs="'0.29 / W'"
sa=0 sb=0 sd=0
model=pfet_01v8
spiceprefix=X
}
C {sky130_fd_pr/nfet3_01v8.sym} 310 -250 3 0 {name=M11
L=0.5
W=3
body=VN
nf=1
mult=1
ad="'int((nf+1)/2) * W/nf * 0.29'" 
pd="'2*int((nf+1)/2) * (W/nf + 0.29)'"
as="'int((nf+2)/2) * W/nf * 0.29'" 
ps="'2*int((nf+2)/2) * (W/nf + 0.29)'"
nrd="'0.29 / W'" nrs="'0.29 / W'"
sa=0 sb=0 sd=0
model=nfet_01v8
spiceprefix=X
}
C {sky130_fd_pr/nfet3_01v8.sym} 2560 -250 3 0 {name=M12
L=0.5
W=3
body=VN
nf=1
mult=1
ad="'int((nf+1)/2) * W/nf * 0.29'" 
pd="'2*int((nf+1)/2) * (W/nf + 0.29)'"
as="'int((nf+2)/2) * W/nf * 0.29'" 
ps="'2*int((nf+2)/2) * (W/nf + 0.29)'"
nrd="'0.29 / W'" nrs="'0.29 / W'"
sa=0 sb=0 sd=0
model=nfet_01v8
spiceprefix=X
}
C {devices/ipin.sym} 170 -650 0 0 {name=p5 lab=V1}
C {devices/ipin.sym} 170 -470 0 0 {name=p1 lab=V2}
C {devices/opin.sym} 2670 -330 0 0 {name=p7 lab=Vout}
C {devices/iopin.sym} 170 -140 0 1 {name=p3 lab=VN}
C {devices/iopin.sym} 170 -750 0 1 {name=p6 lab=Vb}
C {devices/iopin.sym} 170 -940 0 1 {name=p2 lab=VP}
